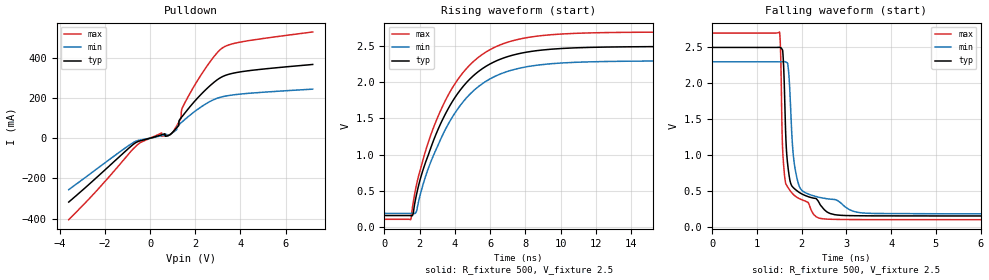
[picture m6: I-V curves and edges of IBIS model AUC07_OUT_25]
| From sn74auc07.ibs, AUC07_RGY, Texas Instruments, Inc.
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[Model]   AUC07_OUT_25
Model_type  Open_drain
Vref =   2.5
Rref =   500
Cref =   30p
Vmeas =   1.25
| variable   typ   min   max
C_comp   4.35pF   1.35pF   13.75pF
| C_pullup   3.20pF   2.76pF   3.51pF
| C_pulldown   5.50pF   1.35pF   13.75pF
[Temperature Range]   40   100   -40
| Ambient temperature   25   85   -40
[Voltage range]   2.5   2.3   2.7
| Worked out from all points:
|   slope of the pulldown table from 0 to 0.375 V, typ, clamps not added: 30.8 ohm
|   falling waveform, R_fixture 500, V_fixture 2.5: 20-80 % time 138ps typ, 189ps min, 99.5ps max; typ from 2.5 V to 0.154 V
|   rising waveform, R_fixture 500, V_fixture 2.5: 20-80 % time 2.79ns typ, 2.8ns min, 2.75ns max; typ from 0.154 V to 2.5 V
[Pulldown]
| AUC07_OUT_25
|   Voltage   I(typ)   I(min)   I(max)
-3.6V     -318.1mA   -256.1mA   -405.8mA
-525mV    -16.28mA   -10.99mA   -29.67mA
515mV     17.24mA    12.98mA    26.06mA
520mV     17.42mA    13.11mA    9.379mA
965mV     25.73mA    24.65mA    24.52mA
1.27V     63.12mA    66.67mA    79.37mA
1.285V    86.1mA     68.16mA    82.34mA
1.37V     100.7mA    76.6mA     99.34mA
1.42V     107.9mA    81.53mA    148.5mA
1.895V    173.8mA    126.1mA    248.7mA
3.16V     304.2mA    205.4mA    446.2mA
7.2V      367.4mA    244.4mA    529.3mA
[Ramp]
| AUC07_OUT_25
| variable   typ   min   max
dV/dt_r   0.03/1.64E-09   0.03/3.75E-09   0.02/1.46E-09
dV/dt_f   1.41/1.42E-10   1.27/1.92E-10   1.57/9.94E-11
R_load = 500
[Falling Waveform]
| AUC07_OUT_25
R_fixture =   500
C_fixture =   0
L_fixture =   0
V_fixture =   2.5
V_fixture_min = 2.3
V_fixture_max = 2.7
|   Time   V(typ)   V(min)   V(max)
0s        2.5V       2.3V       2.7V
1.505ns   2.501V     2.3V       2.715V
1.53ns    2.498V     2.3V       2.383V
1.57ns    2.465V     2.301V     1.128V
1.64ns    1.327V     2.299V     612.2mV
1.735ns   653.9mV    1.887V     511.2mV
1.805ns   553.5mV    1.048V     458.5mV
1.91ns    497.4mV    638.9mV    407.8mV
2.43ns    297.1mV    408.9mV    118.7mV
22ns      154.5mV    184.4mV    102.6mV
[Rising Waveform]
| AUC07_OUT_25
R_fixture =   500
C_fixture =   0
L_fixture =   0
V_fixture =   2.5
V_fixture_min = 2.3
V_fixture_max = 2.7
|   Time   V(typ)   V(min)   V(max)
0s        154.5mV    184.4mV    102.6mV
1.495ns   154.3mV    184.4mV    100.5mV
1.635ns   183.7mV    184.2mV    334.8mV
1.82ns    443.1mV    212.3mV    580.2mV
2.245ns   827.2mV    627.7mV    975.8mV
3.38ns    1.524V     1.31V      1.71V
4.66ns    1.999V     1.787V     2.193V
6.225ns   2.284V     2.078V     2.483V
10.14ns   2.471V     2.27V      2.672V
22ns      2.498V     2.299V     2.699V
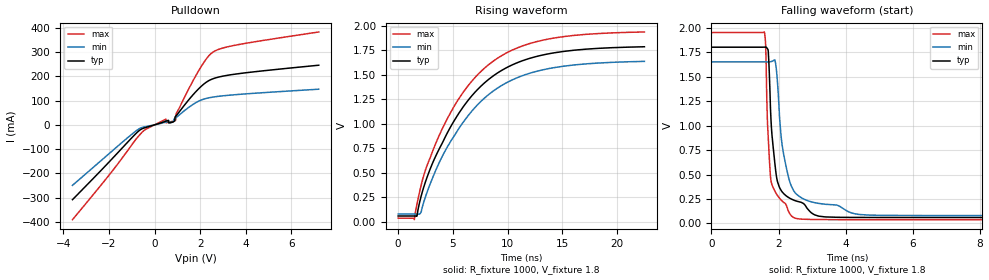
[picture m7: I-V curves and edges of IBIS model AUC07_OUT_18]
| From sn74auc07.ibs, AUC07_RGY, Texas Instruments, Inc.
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[Model]   AUC07_OUT_18
Model_type  Open_drain
Vref =   1.8
Rref =   1000
Cref =   30p
Vmeas =   0.9
| variable   typ   min   max
C_comp   4.13pF   0.76pF   14.74pF
| C_pullup   3.31pF   2.89pF   3.62pF
| C_pulldown   4.96pF   0.76pF   14.74pF
[Temperature Range]   40   100   -40
| Ambient temperature   25   85   -40
[Voltage range]   1.8   1.65   1.95
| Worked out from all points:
|   slope of the pulldown table from 0 to 0.27 V, typ, clamps not added: 34.2 ohm
|   falling waveform, R_fixture 1000, V_fixture 1.8: 20-80 % time 252ps typ, 378ps min, 151ps max; typ from 1.8 V to 0.061 V
|   rising waveform, R_fixture 1000, V_fixture 1.8: 20-80 % time 5.65ns typ, 5.64ns min, 5.58ns max; typ from 0.061 V to 1.79 V
[Pulldown]
| AUC07_OUT_18
|   Voltage   I(typ)   I(min)   I(max)
-3.6V     -307.8mA   -248.9mA   -390.1mA
-520mV    -15mA      -9.825mA   -27.98mA
495mV     15.16mA    11.03mA    23.58mA
505mV     15.48mA    11.26mA    8.542mA
795mV     11.52mA    11.48mA    14.4mA
885mV     16.56mA    25.61mA    16.57mA
925mV     35.08mA    28.52mA    18.81mA
950mV     37.73mA    30.39mA    46.5mA
1.68V     122.9mA    83.75mA    180.2mA
2.515V    187.8mA    113.5mA    296mA
3.51V     208.3mA    123.9mA    327.1mA
7.2V      245.3mA    146.7mA    382.1mA
[Ramp]
| AUC07_OUT_18
| variable   typ   min   max
dV/dt_r   0.03/4.01E-09   0.03/8.71E-09   0.02/3.25E-09
dV/dt_f   1.04/2.56E-10   0.95/3.88E-10   1.15/1.56E-10
R_load = 1000
[Falling Waveform]
| AUC07_OUT_18
R_fixture =   1000
C_fixture =   0
L_fixture =   0
V_fixture =   1.8
V_fixture_min = 1.65
V_fixture_max = 1.95
|   Time   V(typ)   V(min)   V(max)
0s        1.8V       1.65V      1.95V
1.575ns   1.8V       1.65V      1.956V
1.61ns    1.801V     1.65V      1.849V
1.69ns    1.758V     1.649V     879.5mV
1.775ns   1.041V     1.653V     431.2mV
1.975ns   416.8mV    1.397V     281.2mV
2.135ns   310.7mV    735mV      219.7mV
2.495ns   232.7mV    311.9mV    53.45mV
4.695ns   61.35mV    85.26mV    38.75mV
22.5ns    61.05mV    81.01mV    38.68mV
[Rising Waveform]
| AUC07_OUT_18
R_fixture =   1000
C_fixture =   0
L_fixture =   0
V_fixture =   1.8
V_fixture_min = 1.65
V_fixture_max = 1.95
|   Time   V(typ)   V(min)   V(max)
0s        61.05mV    81.01mV    38.68mV
1.48ns    61.07mV    81.01mV    23.8mV
1.715ns   59.77mV    81.04mV    178.7mV
2.08ns    253.7mV    96.56mV    364.4mV
2.405ns   378.3mV    225.7mV    499.2mV
4.145ns   830.6mV    694.6mV    976.8mV
6.19ns    1.212V     1.055V     1.361V
8.505ns   1.475V     1.321V     1.626V
13.55ns   1.712V     1.56V      1.863V
22.5ns    1.788V     1.639V     1.939V
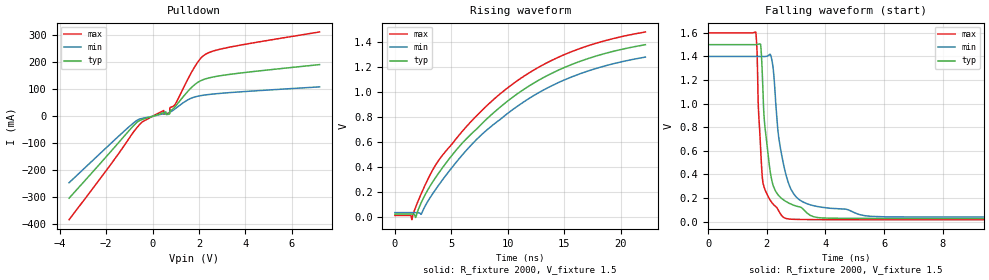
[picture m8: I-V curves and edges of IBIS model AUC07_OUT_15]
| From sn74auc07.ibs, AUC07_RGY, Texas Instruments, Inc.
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[Model]   AUC07_OUT_15
Model_type  Open_drain
Vref =   1.5
Rref =   2000
Cref =   15p
Vmeas =   0.75
| variable   typ   min   max
C_comp   4.13pF   1.72pF   12.92pF
| C_pullup   3.35pF   2.96pF   3.67pF
| C_pulldown   4.91pF   1.72pF   12.92pF
[Temperature Range]   40   100   -40
| Ambient temperature   25   85   -40
[Voltage range]   1.5   1.4   1.6
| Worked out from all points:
|   slope of the pulldown table from 0 to 0.225 V, typ, clamps not added: 37.1 ohm
|   falling waveform, R_fixture 2000, V_fixture 1.5: 20-80 % time 345ps typ, 489ps min, 184ps max; typ from 1.5 V to 0.027 V
|   rising waveform, R_fixture 2000, V_fixture 1.5: 20-80 % time 9.56ns typ, 9.36ns min, 9.57ns max; typ from 0.027 V to 1.38 V
[Pulldown]
| AUC07_OUT_15
|   Voltage   I(typ)   I(min)   I(max)
-3.6V     -303.2mA   -245.9mA   -382.6mA
-680mV    -22.95mA   -15.69mA   -42.71mA
-410mV    -10.84mA   -7.011mA   -19.06mA
480mV     13.54mA    9.64mA     21.5mA
485mV     13.68mA    9.737mA    7.684mA
735mV     9.284mA    14.92mA    12.28mA
750mV     20.66mA    15.42mA    31.62mA
980mV     36.38mA    28.08mA    45.45mA
1.76V     112.9mA    69.91mA    174.9mA
2.205V    136.2mA    78.22mA    225mA
3.25V     154.3mA    87.15mA    254.6mA
7.2V      191.3mA    108.9mA    312.1mA
[Ramp]
| AUC07_OUT_15
| variable   typ   min   max
dV/dt_r   0.03/1.01E-08   0.02/1.95E-08   0.03/8.00E-09
dV/dt_f   0.89/3.52E-10   0.83/4.94E-10   0.96/1.97E-10
R_load = 2000
[Falling Waveform]
| AUC07_OUT_15
R_fixture =   2000
C_fixture =   0
L_fixture =   0
V_fixture =   1.5
V_fixture_min = 1.4
V_fixture_max = 1.6
|   Time   V(typ)   V(min)   V(max)
0s        1.5V       1.4V       1.6V
1.625ns   1.5V       1.4V       1.606V
1.79ns    1.498V     1.4V       611.5mV
1.87ns    1.099V     1.4V       327.9mV
2.165ns   356.3mV    1.378V     164.1mV
2.4ns     222.4mV    726.5mV    93.22mV
2.665ns   168.9mV    386.1mV    26.15mV
3.27ns    97.71mV    162.3mV    17.85mV
5.535ns   27.28mV    45.03mV    16.41mV
22.2ns    27.17mV    38.75mV    16.4mV
[Rising Waveform]
| AUC07_OUT_15
R_fixture =   2000
C_fixture =   0
L_fixture =   0
V_fixture =   1.5
V_fixture_min = 1.4
V_fixture_max = 1.6
|   Time   V(typ)   V(min)   V(max)
0s        27.17mV    38.75mV    16.4mV
1.38ns    27.17mV    38.75mV    15.62mV
1.5ns     27.17mV    38.75mV    -17.53mV
1.845ns   1.525mV    38.77mV    83.29mV
2.33ns    117.3mV    26.28mV    188.7mV
3.7ns     330.7mV    235mV      431.3mV
5.765ns   572.2mV    476.3mV    664.9mV
10.48ns   962.2mV    863.3mV    1.067V
15.7ns    1.221V     1.122V     1.324V
22.2ns    1.378V     1.279V     1.479V
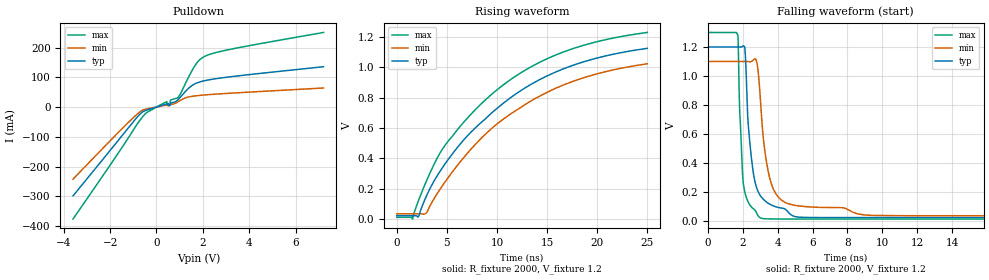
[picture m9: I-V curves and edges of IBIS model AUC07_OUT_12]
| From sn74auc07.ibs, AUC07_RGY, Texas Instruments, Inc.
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[Model]   AUC07_OUT_12
Model_type  Open_drain
Vref =   1.2
Rref =   2000
Cref =   15p
Vmeas =   0.6
| variable   typ   min   max
C_comp   3.79pF   1.97pF   12.54pF
| C_pullup   3.39pF   3.05pF   3.62pF
| C_pulldown   4.19pF   1.97pF   12.54pF
[Temperature Range]   40   100   -40
| Ambient temperature   25   85   -40
[Voltage range]   1.2   1.1   1.3
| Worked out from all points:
|   slope of the pulldown table from 0 to 0.18 V, typ, clamps not added: 42.2 ohm
|   falling waveform, R_fixture 2000, V_fixture 1.2: 20-80 % time 516ps typ, 679ps min, 253ps max; typ from 1.2 V to 0.024 V
|   rising waveform, R_fixture 2000, V_fixture 1.2: 20-80 % time 10.2ns typ, 10ns min, 9.95ns max; typ from 0.024 V to 1.12 V
[Pulldown]
| AUC07_OUT_12
|   Voltage   I(typ)   I(min)   I(max)
-3.6V     -298.5mA   -242.3mA   -376.2mA
-660mV    -19.99mA   -13.21mA   -38.87mA
-370mV    -8.897mA   -5.452mA   -16.12mA
450mV     10.7mA     6.83mA     18.29mA
455mV     10.81mA    6.892mA    6.486mA
590mV     6.193mA    8.414mA    8.677mA
605mV     13.32mA    8.578mA    23.51mA
930mV     24.77mA    17.77mA    32.46mA
1.59V     75.18mA    36.62mA    130.3mA
1.93V     85.77mA    39.62mA    163.2mA
3.005V    99.92mA    45.62mA    191.1mA
7.2V      135.5mA    63.99mA    250.5mA
[Ramp]
| AUC07_OUT_12
| variable   typ   min   max
dV/dt_r   0.02/9.35E-09   0.02/2.02E-08   0.02/7.24E-09
dV/dt_f   0.71/5.21E-10   0.65/6.80E-10   0.77/2.68E-10
R_load = 2000
[Falling Waveform]
| AUC07_OUT_12
R_fixture =   2000
C_fixture =   0
L_fixture =   0
V_fixture =   1.2
V_fixture_min = 1.1
V_fixture_max = 1.3
|   Time   V(typ)   V(min)   V(max)
0s        1.2V       1.1V       1.3V
1.72ns    1.2V       1.1V       1.278V
1.83ns    1.2V       1.1V       732.9mV
2.11ns    1.199V     1.1V       201.9mV
2.47ns    459.2mV    1.099V     100.3mV
2.79ns    230mV      1.099V     56.26mV
3.015ns   173mV      823.9mV    21.78mV
3.585ns   113.8mV    276.7mV    14.9mV
4.67ns    52.07mV    117.2mV    13.97mV
24.99ns   23.98mV    36.61mV    13.86mV
[Rising Waveform]
| AUC07_OUT_12
R_fixture =   2000
C_fixture =   0
L_fixture =   0
V_fixture =   1.2
V_fixture_min = 1.1
V_fixture_max = 1.3
|   Time   V(typ)   V(min)   V(max)
0s        23.98mV    36.61mV    13.86mV
1.585ns   23.98mV    36.61mV    2.385mV
2.17ns    18.21mV    36.62mV    123.5mV
2.955ns   152.2mV    42.19mV    250.5mV
4.385ns   322.3mV    204.4mV    443.3mV
6.1ns     476.1mV    358.5mV    592.7mV
8.555ns   643.7mV    540.6mV    766.5mV
10.88ns   775.2mV    669.9mV    895.2mV
17.01ns   997.8mV    892.1mV    1.108V
24.99ns   1.123V     1.021V     1.227V
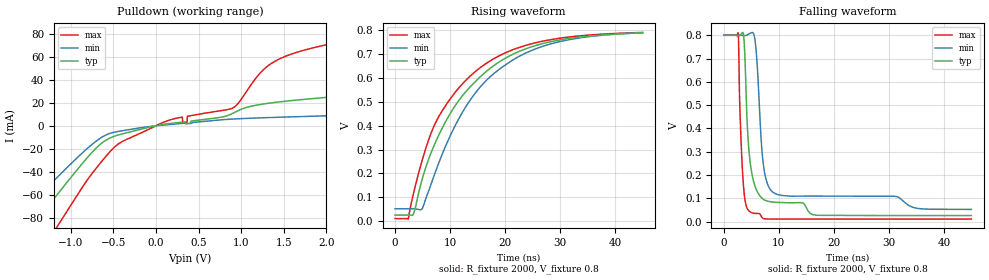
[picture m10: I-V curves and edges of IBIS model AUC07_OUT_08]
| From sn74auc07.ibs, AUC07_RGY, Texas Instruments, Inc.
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[Model]   AUC07_OUT_08
Model_type  Open_drain
Vref =   0.8
Rref =   2000
Cref =   15p
Vmeas =   0.4
| variable   typ   min   max
C_comp   3.62pF   3.17pF   4.09pF
| C_pullup   3.42pF   3.22pF   3.64pF
| C_pulldown   3.82pF   3.17pF   4.09pF
[Temperature Range]   40   100   -40
| Ambient temperature   25   85   -40
[Voltage range]   0.8   0.8   0.8
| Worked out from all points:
|   slope of the pulldown table from 0 to 0.12 V, typ, clamps not added: 76.6 ohm
|   falling waveform, R_fixture 2000, V_fixture 0.8: 20-80 % time 1.4ns typ, 1.36ns min, 745ps max; typ from 0.8 V to 0.025 V
|   rising waveform, R_fixture 2000, V_fixture 0.8: 20-80 % time 12.1ns typ, 12.1ns min, 11.1ns max; typ from 0.025 V to 0.79 V
[Pulldown]
| AUC07_OUT_08
|   Voltage   I(typ)   I(min)   I(max)
-3.6V     -292.2mA   -238.6mA   -365.4mA
-1.78V    -118.8mA   -92.72mA   -159.4mA
-1.5V     -92.12mA   -70.86mA   -127.3mA
-1.155V   -59.55mA   -44.59mA   -87.32mA
-705mV    -19.63mA   -13.53mA   -37.33mA
-420mV    -7.578mA   -4.646mA   -14.81mA
170mV     2.017mA    1.154mA    5.198mA
900mV     10.72mA    5.829mA    15.4mA
1.345V    19.83mA    7.181mA    53.76mA
2.055V    25.05mA    8.779mA    71.49mA
3.215V    31.89mA    11.26mA    87.72mA
7.2V      56.07mA    20.88mA    139.1mA
[Ramp]
| AUC07_OUT_08
| variable   typ   min   max
dV/dt_r   0.01/1.09E-08   0.01/1.91E-08   0.01/9.31E-09
dV/dt_f   0.47/1.39E-09   0.46/1.36E-09   0.48/7.48E-10
R_load = 2000
[Falling Waveform]
| AUC07_OUT_08
R_fixture =   2000
C_fixture =   0
L_fixture =   0
V_fixture =   0.8
V_fixture_min = 0.8
V_fixture_max = 0.8
|   Time   V(typ)   V(min)   V(max)
0s        800mV      800mV      800mV
2.63ns    799.8mV    800mV      807.4mV
2.935ns   798.6mV    800mV      475.7mV
3.46ns    812.1mV    799.5mV    192.3mV
3.735ns   756.7mV    799mV      114.3mV
4.69ns    275.3mV    807.5mV    42.96mV
5.79ns    144.5mV    755.6mV    34.74mV
7.285ns   93.77mV    228.6mV    12.24mV
8.925ns   83.73mV    125.8mV    10.66mV
45ns      25.47mV    52.05mV    10.6mV
[Rising Waveform]
| AUC07_OUT_08
R_fixture =   2000
C_fixture =   0
L_fixture =   0
V_fixture =   0.8
V_fixture_min = 0.8
V_fixture_max = 0.8
|   Time   V(typ)   V(min)   V(max)
0s        25.46mV    51.93mV    10.6mV
2.41ns    25.51mV    51.95mV    8.944mV
3.325ns   29.05mV    52.14mV    112.3mV
4.935ns   175.3mV    52.21mV    254.6mV
8.62ns    392mV      282.8mV    463.9mV
11.96ns   517.3mV    444.6mV    568.3mV
15.52ns   606mV      563.6mV    644.3mV
21.1ns    696.4mV    671.3mV    716.2mV
26.78ns   744.3mV    732.7mV    754.5mV
45ns      789.7mV    790.6mV    791.4mV
